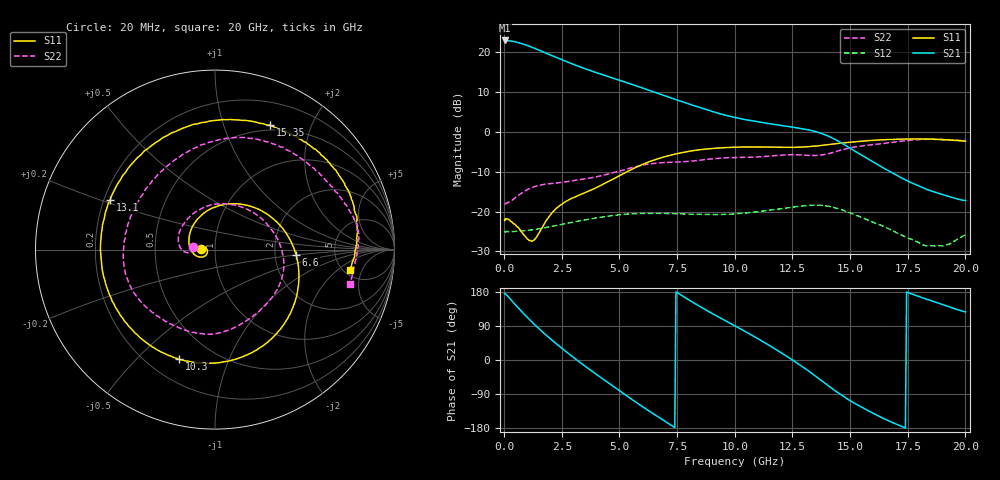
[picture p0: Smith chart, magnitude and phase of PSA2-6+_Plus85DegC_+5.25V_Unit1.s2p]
!Keysight Technologies,N5242A,MY47200155,A.10.49.08
!Date: Thursday, October 19, 2023 15:45:53
!Correction: S11(Full 2 Port(1,2))
!S21(Full 2 Port(1,2))
!S12(Full 2 Port(1,2))
!S22(Full 2 Port(1,2))
!S2P File: Measurements: S11, S21, S12, S22:
# Hz S  dB  R 50
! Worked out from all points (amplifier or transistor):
!   407 points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, 20 MHz to 20 GHz, reference 50 ohm
!   highest |S21| = 22.9 dB at 20 MHz (marker M1)
!   |S21| within 3 dB of that: start of sweep to 1.744 GHz
!   unconditionally stable (mu >= 1): start of sweep to end of sweep
!   at 3.05 GHz: K = 1.13, MAG = 17.5 dB, |S12| = -22.6 dB
!   at 9.85 GHz: K = 1.53, MAG = 7.9 dB, |S12| = -20.7 dB
!   at 20 GHz: K = 11.55, MAG = -9.3 dB, |S12| = -25.8 dB
!   S11 on the Smith chart (normalised r, x): 20 MHz: 0.86, +0.01; 6.6 GHz: 2.63, -0.19; 10.3 GHz: 0.32, -0.67; 13.1 GHz: 0.23, +0.21; 15.35 GHz: 0.44, +1.44; 20 GHz: 5.73, -3.05
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2e7  -22.13 176.1  22.87 175.4  -24.86 -5.0  -18.14 172.9
3e8  -22.54 171.3  22.71 158.6  -25.02 -4.5  -17.32 -174.2
6.5e8  -24.30 166.7  22.27 135.0  -24.92 -9.5  -15.81 -174.4
9e8  -26.11 170.6  21.82 118.9  -24.80 -13.1  -14.85 -178.5
1.2e9  -27.49 -169.0  21.17 100.6  -24.59 -17.5  -13.99 173.8
1.7e9  -23.48 -147.7  19.98 72.1  -24.13 -25.6  -13.23 157.6
2.2e9  -19.52 -158.8  18.76 45.9  -23.55 -34.8  -12.89 137.6
2.75e9  -17.27 178.2  17.47 18.8  -22.93 -46.6  -12.49 114.3
3.35e9  -15.68 149.4  16.12 -9.0  -22.25 -60.2  -11.93 89.7
4.05e9  -13.86 114.1  14.70 -40.1  -21.56 -77.8  -11.23 62.7
4.75e9  -11.77 77.8  13.36 -70.5  -20.96 -96.5  -10.23 36.1
5.7e9  -8.96 32.3  11.55 -110.8  -20.53 -123.2  -8.75 3.3
6.6e9  -6.90 -3.6  9.75 -147.3  -20.47 -147.9  -7.86 -22.4
6.7e9  -6.71 -7.2  9.55 -151.3  -20.45 -150.6  -7.82 -25.1
8.3e9  -4.66 -56.4  6.41 148.0  -20.68 167.8  -7.24 -66.8
1.005e10  -3.88 -101.8  3.52 88.4  -20.55 127.5  -6.47 -100.7
1.03e10  -3.84 -108.2  3.22 80.3  -20.43 121.6  -6.41 -105.7
1.31e10  -3.79 154.7  0.58 -24.8  -18.53 42.3  -5.94 173.0
1.335e10  -3.68 143.5  0.27 -35.8  -18.43 33.1  -6.00 161.0
1.535e10  -2.41 66.1  -5.35 -119.7  -21.09 -38.4  -3.67 71.0
1.67e10  -1.96 37.9  -9.88 -161.2  -24.39 -73.8  -2.77 32.7
2e10  -2.36 -8.4  -17.25 126.7  -25.81 -101.2  -2.22 -14.5
